VERSION 5.7 ;
  NOWIREEXTENSIONATPIN ON ;
  DIVIDERCHAR "/" ;
  BUSBITCHARS "[]" ;
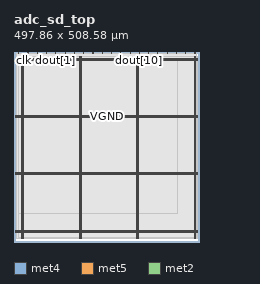
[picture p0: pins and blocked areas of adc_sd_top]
MACRO adc_sd_top
  CLASS BLOCK ;
  FOREIGN adc_sd_top ;
  ORIGIN 0.000 0.000 ;
  SIZE 497.860 BY 508.580 ;
  PIN VGND
    DIRECTION INOUT ;
    USE GROUND ;
    PORT
      LAYER met4 ;
        RECT 24.340 10.640 25.940 495.280 ;
    END
    PORT
      LAYER met4 ;
        RECT 177.940 10.640 179.540 495.280 ;
    END
    PORT
      LAYER met4 ;
        RECT 331.540 10.640 333.140 495.280 ;
    END
    PORT
      LAYER met4 ;
        RECT 485.140 10.640 486.740 495.280 ;
    END
    PORT
      LAYER met5 ;
        RECT 5.280 30.030 492.440 31.630 ;
    END
    PORT
      LAYER met5 ;
        RECT 5.280 183.210 492.440 184.810 ;
    END
    PORT
      LAYER met5 ;
        RECT 5.280 336.390 492.440 337.990 ;
    END
    PORT
      LAYER met5 ;
        RECT 5.280 489.570 492.440 491.170 ;
    END
  END VGND
  PIN VPWR
    DIRECTION INOUT ;
    USE POWER ;
    PORT
      LAYER met4 ;
        RECT 21.040 10.640 22.640 495.280 ;
    END
    PORT
      LAYER met4 ;
        RECT 174.640 10.640 176.240 495.280 ;
    END
    PORT
      LAYER met4 ;
        RECT 328.240 10.640 329.840 495.280 ;
    END
    PORT
      LAYER met4 ;
        RECT 481.840 10.640 483.440 495.280 ;
    END
    PORT
      LAYER met5 ;
        RECT 5.280 26.730 492.440 28.330 ;
    END
    PORT
      LAYER met5 ;
        RECT 5.280 179.910 492.440 181.510 ;
    END
    PORT
      LAYER met5 ;
        RECT 5.280 333.090 492.440 334.690 ;
    END
    PORT
      LAYER met5 ;
        RECT 5.280 486.270 492.440 487.870 ;
    END
  END VPWR
  PIN clk
    DIRECTION INPUT ;
    USE SIGNAL ;
    ANTENNAGATEAREA 0.852000 ;
    ANTENNADIFFAREA 0.434700 ;
    PORT
      LAYER met2 ;
        RECT 12.510 504.580 12.790 508.580 ;
    END
  END clk
  PIN din
    DIRECTION INPUT ;
    USE SIGNAL ;
    ANTENNAGATEAREA 0.213000 ;
    PORT
      LAYER met2 ;
        RECT 62.190 504.580 62.470 508.580 ;
    END
  END din
  PIN dout[0]
    DIRECTION OUTPUT ;
    USE SIGNAL ;
    ANTENNADIFFAREA 0.795200 ;
    PORT
      LAYER met2 ;
        RECT 87.030 504.580 87.310 508.580 ;
    END
  END dout[0]
  PIN dout[10]
    DIRECTION OUTPUT ;
    USE SIGNAL ;
    ANTENNADIFFAREA 0.795200 ;
    PORT
      LAYER met2 ;
        RECT 335.430 504.580 335.710 508.580 ;
    END
  END dout[10]
  PIN dout[11]
    DIRECTION OUTPUT ;
    USE SIGNAL ;
    ANTENNADIFFAREA 0.795200 ;
    PORT
      LAYER met2 ;
        RECT 360.270 504.580 360.550 508.580 ;
    END
  END dout[11]
  PIN dout[12]
    DIRECTION OUTPUT ;
    USE SIGNAL ;
    ANTENNADIFFAREA 0.795200 ;
    PORT
      LAYER met2 ;
        RECT 385.110 504.580 385.390 508.580 ;
    END
  END dout[12]
  PIN dout[13]
    DIRECTION OUTPUT ;
    USE SIGNAL ;
    ANTENNADIFFAREA 0.795200 ;
    PORT
      LAYER met2 ;
        RECT 409.950 504.580 410.230 508.580 ;
    END
  END dout[13]
  PIN dout[14]
    DIRECTION OUTPUT ;
    USE SIGNAL ;
    ANTENNADIFFAREA 0.795200 ;
    PORT
      LAYER met2 ;
        RECT 434.790 504.580 435.070 508.580 ;
    END
  END dout[14]
  PIN dout[15]
    DIRECTION OUTPUT ;
    USE SIGNAL ;
    ANTENNADIFFAREA 0.795200 ;
    PORT
      LAYER met2 ;
        RECT 459.630 504.580 459.910 508.580 ;
    END
  END dout[15]
  PIN dout[1]
    DIRECTION OUTPUT ;
    USE SIGNAL ;
    ANTENNADIFFAREA 0.795200 ;
    PORT
      LAYER met2 ;
        RECT 111.870 504.580 112.150 508.580 ;
    END
  END dout[1]
  PIN dout[2]
    DIRECTION OUTPUT ;
    USE SIGNAL ;
    ANTENNADIFFAREA 0.795200 ;
    PORT
      LAYER met2 ;
        RECT 136.710 504.580 136.990 508.580 ;
    END
  END dout[2]
  PIN dout[3]
    DIRECTION OUTPUT ;
    USE SIGNAL ;
    ANTENNADIFFAREA 0.795200 ;
    PORT
      LAYER met2 ;
        RECT 161.550 504.580 161.830 508.580 ;
    END
  END dout[3]
  PIN dout[4]
    DIRECTION OUTPUT ;
    USE SIGNAL ;
    ANTENNADIFFAREA 0.795200 ;
    PORT
      LAYER met2 ;
        RECT 186.390 504.580 186.670 508.580 ;
    END
  END dout[4]
  PIN dout[5]
    DIRECTION OUTPUT ;
    USE SIGNAL ;
    ANTENNADIFFAREA 0.795200 ;
    PORT
      LAYER met2 ;
        RECT 211.230 504.580 211.510 508.580 ;
    END
  END dout[5]
  PIN dout[6]
    DIRECTION OUTPUT ;
    USE SIGNAL ;
    ANTENNADIFFAREA 0.795200 ;
    PORT
      LAYER met2 ;
        RECT 236.070 504.580 236.350 508.580 ;
    END
  END dout[6]
  PIN dout[7]
    DIRECTION OUTPUT ;
    USE SIGNAL ;
    ANTENNADIFFAREA 0.795200 ;
    PORT
      LAYER met2 ;
        RECT 260.910 504.580 261.190 508.580 ;
    END
  END dout[7]
  PIN dout[8]
    DIRECTION OUTPUT ;
    USE SIGNAL ;
    ANTENNADIFFAREA 0.795200 ;
    PORT
      LAYER met2 ;
        RECT 285.750 504.580 286.030 508.580 ;
    END
  END dout[8]
  PIN dout[9]
    DIRECTION OUTPUT ;
    USE SIGNAL ;
    ANTENNADIFFAREA 0.795200 ;
    PORT
      LAYER met2 ;
        RECT 310.590 504.580 310.870 508.580 ;
    END
  END dout[9]
  PIN dout_valid
    DIRECTION OUTPUT ;
    USE SIGNAL ;
    ANTENNADIFFAREA 0.795200 ;
    PORT
      LAYER met2 ;
        RECT 484.470 504.580 484.750 508.580 ;
    END
  END dout_valid
  PIN rst_n
    DIRECTION INPUT ;
    USE SIGNAL ;
    ANTENNAGATEAREA 0.213000 ;
    PORT
      LAYER met2 ;
        RECT 37.350 504.580 37.630 508.580 ;
    END
  END rst_n
  OBS
      LAYER li1 ;
        RECT 5.520 10.795 492.200 495.125 ;
      LAYER met1 ;
        RECT 5.520 10.640 492.200 496.360 ;
      LAYER met2 ;
        RECT 7.920 504.300 12.230 504.580 ;
        RECT 13.070 504.300 37.070 504.580 ;
        RECT 37.910 504.300 61.910 504.580 ;
        RECT 62.750 504.300 86.750 504.580 ;
        RECT 87.590 504.300 111.590 504.580 ;
        RECT 112.430 504.300 136.430 504.580 ;
        RECT 137.270 504.300 161.270 504.580 ;
        RECT 162.110 504.300 186.110 504.580 ;
        RECT 186.950 504.300 210.950 504.580 ;
        RECT 211.790 504.300 235.790 504.580 ;
        RECT 236.630 504.300 260.630 504.580 ;
        RECT 261.470 504.300 285.470 504.580 ;
        RECT 286.310 504.300 310.310 504.580 ;
        RECT 311.150 504.300 335.150 504.580 ;
        RECT 335.990 504.300 359.990 504.580 ;
        RECT 360.830 504.300 384.830 504.580 ;
        RECT 385.670 504.300 409.670 504.580 ;
        RECT 410.510 504.300 434.510 504.580 ;
        RECT 435.350 504.300 459.350 504.580 ;
        RECT 460.190 504.300 484.190 504.580 ;
        RECT 485.030 504.300 489.800 504.580 ;
        RECT 7.920 10.695 489.800 504.300 ;
      LAYER met3 ;
        RECT 12.485 10.715 486.730 495.205 ;
      LAYER met4 ;
        RECT 13.175 76.335 20.640 490.785 ;
        RECT 23.040 76.335 23.940 490.785 ;
        RECT 26.340 76.335 174.240 490.785 ;
        RECT 176.640 76.335 177.540 490.785 ;
        RECT 179.940 76.335 327.840 490.785 ;
        RECT 330.240 76.335 331.140 490.785 ;
        RECT 333.540 76.335 437.625 490.785 ;
  END
END adc_sd_top
END LIBRARY

